One B-rep face of a CAD part: STEP entity #158.
In plain terms, the planar face has unit normal (0, 0, -1).
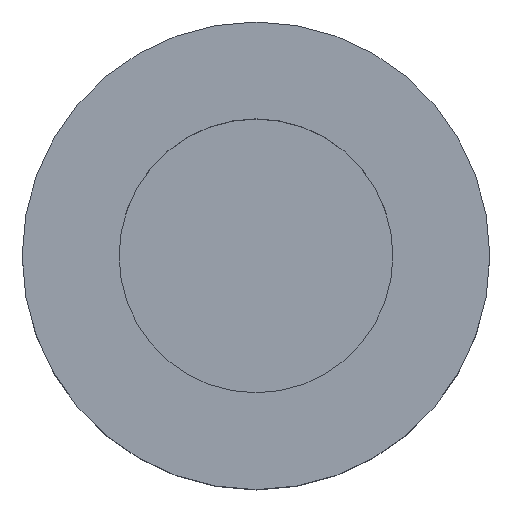
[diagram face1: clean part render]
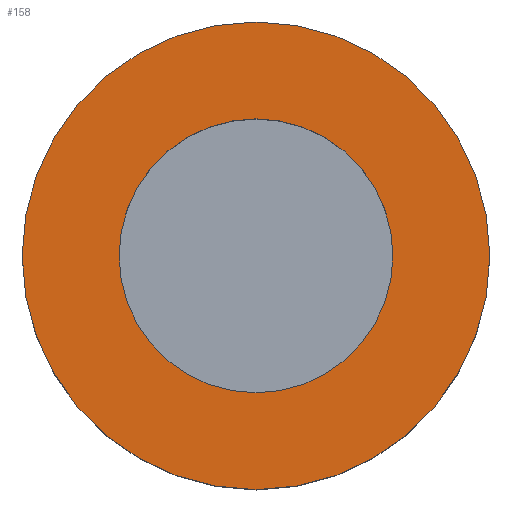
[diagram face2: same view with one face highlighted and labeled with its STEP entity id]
Its self-contained STEP definition (entity closure, numbers rounded to 3 decimals):
#49 = CYLINDRICAL_SURFACE('',#50,7.);
#50 = AXIS2_PLACEMENT_3D('',#51,#52,#53);
#51 = CARTESIAN_POINT('',(0.,0.,-3.));
#52 = DIRECTION('',(0.,0.,1.));
#53 = DIRECTION('',(1.,0.,-0.));
#74 = VERTEX_POINT('',#75);
#75 = CARTESIAN_POINT('',(7.,0.,-3.));
#96 = EDGE_CURVE('',#74,#74,#97,.T.);
#97 = SURFACE_CURVE('',#98,(#103,#110),.PCURVE_S1.);
#98 = CIRCLE('',#99,7.);
#99 = AXIS2_PLACEMENT_3D('',#100,#101,#102);
#100 = CARTESIAN_POINT('',(0.,0.,-3.));
#101 = DIRECTION('',(0.,0.,1.));
#102 = DIRECTION('',(1.,0.,-0.));
#103 = PCURVE('',#49,#104);
#104 = DEFINITIONAL_REPRESENTATION('',(#105),#109);
#105 = LINE('',#106,#107);
#106 = CARTESIAN_POINT('',(0.,0.));
#107 = VECTOR('',#108,1.);
#108 = DIRECTION('',(1.,0.));
#109 = ( GEOMETRIC_REPRESENTATION_CONTEXT(2) 
PARAMETRIC_REPRESENTATION_CONTEXT() REPRESENTATION_CONTEXT('2D SPACE',''
  ) );
#110 = PCURVE('',#111,#116);
#111 = PLANE('',#112);
#112 = AXIS2_PLACEMENT_3D('',#113,#114,#115);
#113 = CARTESIAN_POINT('',(0.,0.,-3.));
#114 = DIRECTION('',(0.,0.,1.));
#115 = DIRECTION('',(1.,0.,-0.));
#116 = DEFINITIONAL_REPRESENTATION('',(#117),#121);
#117 = CIRCLE('',#118,7.);
#118 = AXIS2_PLACEMENT_2D('',#119,#120);
#119 = CARTESIAN_POINT('',(0.,0.));
#120 = DIRECTION('',(1.,0.));
#121 = ( GEOMETRIC_REPRESENTATION_CONTEXT(2) 
PARAMETRIC_REPRESENTATION_CONTEXT() REPRESENTATION_CONTEXT('2D SPACE',''
  ) );
#158 = ADVANCED_FACE('',(#159,#162),#111,.F.);
#159 = FACE_BOUND('',#160,.F.);
#160 = EDGE_LOOP('',(#161));
#161 = ORIENTED_EDGE('',*,*,#96,.T.);
#162 = FACE_BOUND('',#163,.F.);
#163 = EDGE_LOOP('',(#164));
#164 = ORIENTED_EDGE('',*,*,#165,.F.);
#165 = EDGE_CURVE('',#166,#166,#168,.T.);
#166 = VERTEX_POINT('',#167);
#167 = CARTESIAN_POINT('',(4.1,0.,-3.));
#168 = SURFACE_CURVE('',#169,(#174,#181),.PCURVE_S1.);
#169 = CIRCLE('',#170,4.1);
#170 = AXIS2_PLACEMENT_3D('',#171,#172,#173);
#171 = CARTESIAN_POINT('',(0.,0.,-3.));
#172 = DIRECTION('',(0.,0.,1.));
#173 = DIRECTION('',(1.,0.,-0.));
#174 = PCURVE('',#111,#175);
#175 = DEFINITIONAL_REPRESENTATION('',(#176),#180);
#176 = CIRCLE('',#177,4.1);
#177 = AXIS2_PLACEMENT_2D('',#178,#179);
#178 = CARTESIAN_POINT('',(0.,0.));
#179 = DIRECTION('',(1.,0.));
#180 = ( GEOMETRIC_REPRESENTATION_CONTEXT(2) 
PARAMETRIC_REPRESENTATION_CONTEXT() REPRESENTATION_CONTEXT('2D SPACE',''
  ) );
#181 = PCURVE('',#182,#187);
#182 = CYLINDRICAL_SURFACE('',#183,4.1);
#183 = AXIS2_PLACEMENT_3D('',#184,#185,#186);
#184 = CARTESIAN_POINT('',(0.,0.,-4.));
#185 = DIRECTION('',(0.,0.,1.));
#186 = DIRECTION('',(1.,0.,-0.));
#187 = DEFINITIONAL_REPRESENTATION('',(#188),#192);
#188 = LINE('',#189,#190);
#189 = CARTESIAN_POINT('',(0.,1.));
#190 = VECTOR('',#191,1.);
#191 = DIRECTION('',(1.,0.));
#192 = ( GEOMETRIC_REPRESENTATION_CONTEXT(2) 
PARAMETRIC_REPRESENTATION_CONTEXT() REPRESENTATION_CONTEXT('2D SPACE',''
  ) );
